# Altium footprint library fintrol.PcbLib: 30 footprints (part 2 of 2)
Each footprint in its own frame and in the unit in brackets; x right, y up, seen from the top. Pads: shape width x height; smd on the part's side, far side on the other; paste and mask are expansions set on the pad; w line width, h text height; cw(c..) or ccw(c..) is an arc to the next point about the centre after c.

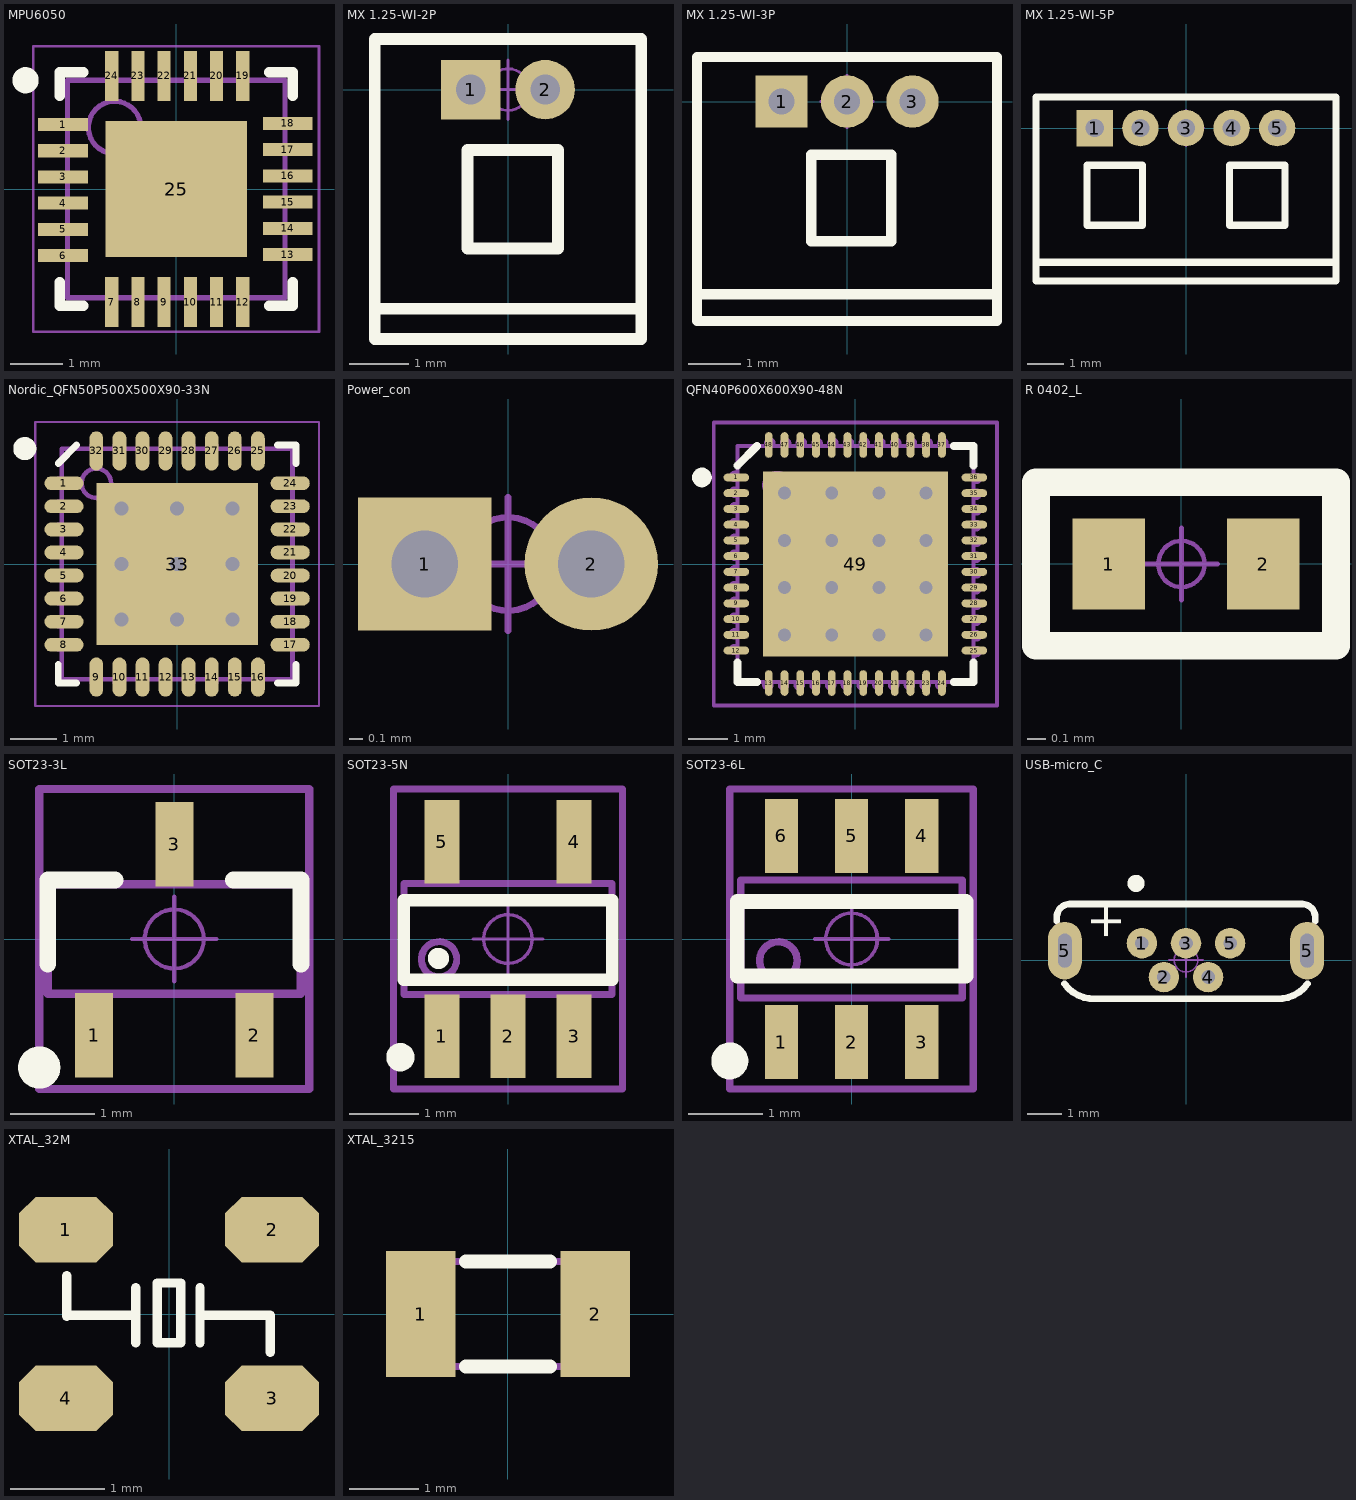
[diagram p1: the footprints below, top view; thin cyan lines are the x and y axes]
## MPU6050 [mm] "QFN, 24-Leads, Body 4.00x4.00mm, Pitch 0.50mm, Thermal Pad 2.70x2.60mm, IPC Medium Density"
height 0.9
pads (25):
  rect 0.95x0.25 smd: 1(-2.159,1.23) 2(-2.159,0.73) 3(-2.159,0.23) 4(-2.159,-0.27) 5(-2.159,-0.77) 6(-2.159,-1.27) 13(2.127,-1.25) 14(2.127,-0.75) 15(2.127,-0.25) 16(2.127,0.25) 17(2.127,0.75) 18(2.127,1.25)
  rect 0.25x0.95 smd: 7(-1.23,-2.159) 8(-0.73,-2.159) 9(-0.23,-2.159) 10(0.27,-2.159) 11(0.77,-2.159) 12(1.27,-2.159) 19(1.27,2.159) 20(0.77,2.159) 21(0.27,2.159) 22(-0.23,2.159) 23(-0.73,2.159) 24(-1.23,2.159)
  rect 2.7x2.6 smd: 25(0,0)
Top Overlay:
  circle w0.25: c-2.875,2.075 r0.125
  lines w0.2: -2.225,-1.775 -2.225,-2.225 -1.775,-2.225 ; -2.225,1.775 -2.225,2.225 -1.775,2.225 ; 1.775,-2.225 2.225,-2.225 2.225,-1.775 ; 1.775,2.225 2.225,2.225 2.225,1.775
Mechanical 13:
  circle w0.1: c-1.175,1.175 r0.5
  lines w0.1: -2.075,-2.075 2.075,-2.075 2.075,2.075 -2.075,2.075 -2.075,-2.075
Mechanical 15:
  lines w0.05: -2.725,-2.725 2.725,-2.725 2.725,2.725 -2.725,2.725 -2.725,-2.725
  lines w0.1: -0.5,0 0.5,0 ; 0,-0.5 0,0.5
3D body: height 0.9, standoff 0.01, extent -2.075,-2.075 2.075,2.075

## MX 1.25-WI-2P [mm] "长：4.25mm，宽：1.8mm，高：3.3mm"
pads (2):
  rect 1x1 hole 0.5: 1(-0.625,0)
  round 1 hole 0.5: 2(0.625,0)
Top Overlay:
  lines w0.2: -2.239,-3.683 2.239,-3.683 ; -2.239,-4.191 -2.239,0.85 2.239,0.85 2.239,-4.191 -2.239,-4.191 ; -0.682,-2.667 -0.682,-1.016 0.842,-1.016 0.842,-2.667 -0.682,-2.667
Mechanical 15:
  circle w0.05: c0,0 r0.35
  lines w0.05: -0.5,0 0.5,0 ; 0,-0.5 0,0.5
3D body "MOLEX1.25-WI-2P.STEP": height 3.35, standoff -2.1, extent -2.125,-4.05 2.125,0.85

## MX 1.25-WI-3P [mm] "长：5.5mm，宽：1.8mm，高：3.3mm"
pads (3):
  rect 1x1 hole 0.5: 1(-1.25,0)
  round 1 hole 0.5: 2(0,0) 3(1.25,0)
Top Overlay:
  lines w0.2: -2.864,-3.683 2.864,-3.683 ; -2.864,-4.191 2.864,-4.191 2.864,0.85 -2.864,0.85 -2.864,-4.191 ; -0.682,-2.667 0.842,-2.667 0.842,-1.016 -0.682,-1.016 -0.682,-2.667
Mechanical 15:
  circle w0.05: c0,0 r0.35
  lines w0.05: -0.5,0 0.5,0 ; 0,-0.5 0,0.5
3D body "MOLEX1.25-WI-3P.STEP": height 3.35, standoff -2.1, extent -2.75,-4.05 2.75,0.85

## MX 1.25-WI-5P [mm] "长：8mm，宽：1.8mm，高：3.3mm"
pads (5):
  rect 1x1 hole 0.5: 1(-2.5,0)
  round 1 hole 0.5: 2(-1.25,0) 3(0,0) 4(1.25,0) 5(2.5,0)
Top Overlay:
  lines w0.2: -4.114,-3.683 4.114,-3.683 ; -4.114,-4.191 4.114,-4.191 4.114,0.85 -4.114,0.85 -4.114,-4.191 ; -2.717,-2.667 -2.717,-1.016 -1.193,-1.016 -1.193,-2.667 -2.717,-2.667 ; 1.193,-2.667 1.193,-1.016 2.717,-1.016 2.717,-2.667 1.193,-2.667
Mechanical 15:
  circle w0.05: c0,0 r0.35
  lines w0.05: -0.5,0 0.5,0 ; 0,-0.5 0,0.5
3D body "MOLEX1.25-WI-5P.STEP": height 3.35, standoff -2.1, extent -4,-4.05 4,0.85

## Nordic_QFN50P500X500X90-33N [mm]
pads (33):
  oval 0.85x0.3 smd mask+0.076: 1(-2.45,1.75) 2(-2.45,1.25) 3(-2.45,0.75) 4(-2.45,0.25) 5(-2.45,-0.25) 6(-2.45,-0.75) 7(-2.45,-1.25) 8(-2.45,-1.75) 17(2.45,-1.75) 18(2.45,-1.25) 19(2.45,-0.75) 20(2.45,-0.25) 21(2.45,0.25) 22(2.45,0.75) 23(2.45,1.25) 24(2.45,1.75)
  oval 0.3x0.85 smd mask+0.076: 9(-1.75,-2.45) 10(-1.25,-2.45) 11(-0.75,-2.45) 12(-0.25,-2.45) 13(0.25,-2.45) 14(0.75,-2.45) 15(1.25,-2.45) 16(1.75,-2.45) 25(1.75,2.45) 26(1.25,2.45) 27(0.75,2.45) 28(0.25,2.45) 29(-0.25,2.45) 30(-0.75,2.45) 31(-1.25,2.45) 32(-1.75,2.45)
  rect 3.5x3.5 smd: 33(0,0)
via 1.2,1.2 diameter 0.61 hole 0.305
via 1.2,0 diameter 0.61 hole 0.305
via 1.2,-1.2 diameter 0.61 hole 0.305
via 0,-1.2 diameter 0.61 hole 0.305
via -1.2,-1.2 diameter 0.61 hole 0.305
via -1.2,0 diameter 0.61 hole 0.305
via -1.2,1.2 diameter 0.61 hole 0.305
via 0,1.2 diameter 0.61 hole 0.305
via 0,0 diameter 0.61 hole 0.305
Top Overlay:
  circle w0.25: c-3.3,2.5 r0.125
  lines w0.15: -2.575,-2.175 -2.575,-2.575 -2.175,-2.575 ; -2.575,2.175 -2.175,2.575 ; 2.175,-2.575 2.575,-2.575 2.575,-2.175 ; 2.175,2.575 2.575,2.575 2.575,2.175
Mechanical 7:
  circle w0.1: c-1.75,1.75 r0.32
  lines w0.1: -2.5,-1.845 -2.571,-1.845 cw(c-2.571,-1.75) -2.571,-1.655 -2.5,-1.655 ; -2.5,-1.345 -2.571,-1.345 cw(c-2.571,-1.25) -2.571,-1.155 -2.5,-1.155 ; -2.5,-0.845 -2.571,-0.845 cw(c-2.571,-0.75) -2.571,-0.655 -2.5,-0.655 ; -2.5,-0.345 -2.571,-0.345 cw(c-2.571,-0.25) -2.571,-0.155 -2.5,-0.155 ; -2.5,0.155 -2.571,0.155 cw(c-2.571,0.25) -2.571,0.345 -2.5,0.345 ; -2.5,0.655 -2.571,0.655 cw(c-2.571,0.75) -2.571,0.845 -2.5,0.845 ; -2.5,1.155 -2.571,1.155 cw(c-2.571,1.25) -2.571,1.345 -2.5,1.345 ; -2.5,1.655 -2.571,1.655 cw(c-2.571,1.75) -2.571,1.845 -2.5,1.845 ; -1.845,-2.5 -1.845,-2.571 ccw(c-1.75,-2.571) -1.655,-2.571 -1.655,-2.5 ; -1.845,2.5 -1.845,2.571 cw(c-1.75,2.571) -1.655,2.571 -1.655,2.5 ; -1.345,-2.5 -1.345,-2.571 ccw(c-1.25,-2.571) -1.155,-2.571 -1.155,-2.5 ; -1.345,2.5 -1.345,2.571 cw(c-1.25,2.571) -1.155,2.571 -1.155,2.5 ; -0.845,-2.5 -0.845,-2.571 ccw(c-0.75,-2.571) -0.655,-2.571 -0.655,-2.5 ; -0.845,2.5 -0.845,2.571 cw(c-0.75,2.571) -0.655,2.571 -0.655,2.5 ; -0.345,-2.5 -0.345,-2.571 ccw(c-0.25,-2.571) -0.155,-2.571 -0.155,-2.5 ; -0.345,2.5 -0.345,2.571 cw(c-0.25,2.571) -0.155,2.571 -0.155,2.5 ; 0.155,-2.5 0.155,-2.571 ccw(c0.25,-2.571) 0.345,-2.571 0.345,-2.5 ; 0.155,2.5 0.155,2.571 cw(c0.25,2.571) 0.345,2.571 0.345,2.5 ; 0.655,-2.5 0.655,-2.571 ccw(c0.75,-2.571) 0.845,-2.571 0.845,-2.5 ; 0.655,2.5 0.655,2.571 cw(c0.75,2.571) 0.845,2.571 0.845,2.5 ; 1.155,-2.5 1.155,-2.571 ccw(c1.25,-2.571) 1.345,-2.571 1.345,-2.5 ; 1.155,2.5 1.155,2.571 cw(c1.25,2.571) 1.345,2.571 1.345,2.5 ; 1.655,-2.5 1.655,-2.571 ccw(c1.75,-2.571) 1.845,-2.571 1.845,-2.5 ; 1.655,2.5 1.655,2.571 cw(c1.75,2.571) 1.845,2.571 1.845,2.5 ; 2.5,-1.845 2.571,-1.845 ccw(c2.571,-1.75) 2.571,-1.655 2.5,-1.655 ; 2.5,-1.345 2.571,-1.345 ccw(c2.571,-1.25) 2.571,-1.155 2.5,-1.155 ; 2.5,-0.845 2.571,-0.845 ccw(c2.571,-0.75) 2.571,-0.655 2.5,-0.655 ; 2.5,-0.345 2.571,-0.345 ccw(c2.571,-0.25) 2.571,-0.155 2.5,-0.155 ; 2.5,0.155 2.571,0.155 ccw(c2.571,0.25) 2.571,0.345 2.5,0.345 ; 2.5,0.655 2.571,0.655 ccw(c2.571,0.75) 2.571,0.845 2.5,0.845 ; 2.5,1.155 2.571,1.155 ccw(c2.571,1.25) 2.571,1.345 2.5,1.345 ; 2.5,1.655 2.571,1.655 ccw(c2.571,1.75) 2.571,1.845 2.5,1.845 ; -2.5,-2.5 2.5,-2.5 2.5,2.5 -2.5,2.5 -2.5,-2.5
  text ".Designator" at -0.879,-0.131 h0.38
Mechanical 15:
  lines w0.05: -3.075,-3.075 -3.075,3.075 3.075,3.075 3.075,-3.075 -3.075,-3.075
  lines w0.1: -0.5,0 0.5,0 ; 0,-0.5 0,0.5
3D body "QFN50P500X500X90_HS-33N.step": height 0.9, standoff 0, extent -2.501,-2.501 2.501,2.501

## Power_con [mm] "长：4.25mm，宽：1.8mm，高：3.3mm"
pads (2):
  rect 1x1 hole 0.5: 1(-0.625,0)
  round 1 hole 0.5: 2(0.625,0)
Mechanical 15:
  circle w0.05: c0,0 r0.35
  lines w0.05: -0.5,0 0.5,0 ; 0,-0.5 0,0.5

## QFN40P600X600X90-48N [mm]
pads (49):
  oval 0.65x0.2 smd: 1(-3.025,2.2) 2(-3.025,1.8) 3(-3.025,1.4) 4(-3.025,1) 5(-3.025,0.6) 6(-3.025,0.2) 7(-3.025,-0.2) 8(-3.025,-0.6) 9(-3.025,-1) 10(-3.025,-1.4) 11(-3.025,-1.8) 12(-3.025,-2.2) 25(3.025,-2.2) 26(3.025,-1.8) 27(3.025,-1.4) 28(3.025,-1) 29(3.025,-0.6) 30(3.025,-0.2) 31(3.025,0.2) 32(3.025,0.6) 33(3.025,1) 34(3.025,1.4) 35(3.025,1.8) 36(3.025,2.2)
  oval 0.2x0.65 smd: 13(-2.2,-3.025) 14(-1.8,-3.025) 15(-1.4,-3.025) 16(-1,-3.025) 17(-0.6,-3.025) 18(-0.2,-3.025) 19(0.2,-3.025) 20(0.6,-3.025) 21(1,-3.025) 22(1.4,-3.025) 23(1.8,-3.025) 24(2.2,-3.025) 37(2.2,3.025) 38(1.8,3.025) 39(1.4,3.025) 40(1,3.025) 41(0.6,3.025) 42(0.2,3.025) 43(-0.2,3.025) 44(-0.6,3.025) 45(-1,3.025) 46(-1.4,3.025) 47(-1.8,3.025) 48(-2.2,3.025)
  rect 4.7x4.7 smd: 49(0,0)
via -1.8,1.8 diameter 0.66 hole 0.33
via -0.6,1.8 diameter 0.66 hole 0.33
via 0.6,1.8 diameter 0.66 hole 0.33
via 1.8,1.8 diameter 0.66 hole 0.33
via -1.8,0.6 diameter 0.66 hole 0.33
via -0.6,0.6 diameter 0.66 hole 0.33
via 0.6,0.6 diameter 0.66 hole 0.33
via 1.8,0.6 diameter 0.66 hole 0.33
via -1.8,-0.6 diameter 0.66 hole 0.33
via -0.6,-0.6 diameter 0.66 hole 0.33
via 0.6,-0.6 diameter 0.66 hole 0.33
via 1.8,-0.6 diameter 0.66 hole 0.33
via -1.8,-1.8 diameter 0.66 hole 0.33
via -0.6,-1.8 diameter 0.66 hole 0.33
via 0.6,-1.8 diameter 0.66 hole 0.33
via 1.8,-1.8 diameter 0.66 hole 0.33
Top Overlay:
  circle w0.25: c-3.9,2.2 r0.125
  lines w0.2: -3,-2.5 -3,-3 -2.5,-3 ; -3,2.5 -2.5,3 ; 2.5,-3 3,-3 3,-2.5 ; 2.5,3 3,3 3,2.5
Mechanical 7:
  circle w0.1: c-2,2 r0.32
  lines w0.1: -3,-2.269 -3.071,-2.269 cw(c-3.071,-2.174) -3.071,-2.079 -3,-2.079 ; -3,-1.869 -3.071,-1.869 cw(c-3.071,-1.774) -3.071,-1.679 -3,-1.679 ; -3,-1.469 -3.071,-1.469 cw(c-3.071,-1.374) -3.071,-1.279 -3,-1.279 ; -3,-1.069 -3.071,-1.069 cw(c-3.071,-0.974) -3.071,-0.879 -3,-0.879 ; -3,-0.669 -3.071,-0.669 cw(c-3.071,-0.574) -3.071,-0.479 -3,-0.479 ; -3,-0.269 -3.071,-0.269 cw(c-3.071,-0.174) -3.071,-0.079 -3,-0.079 ; -3,0.131 -3.071,0.131 cw(c-3.071,0.226) -3.071,0.321 -3,0.321 ; -3,0.531 -3.071,0.531 cw(c-3.071,0.626) -3.071,0.721 -3,0.721 ; -3,0.931 -3.071,0.931 cw(c-3.071,1.026) -3.071,1.121 -3,1.121 ; -3,1.331 -3.071,1.331 cw(c-3.071,1.426) -3.071,1.521 -3,1.521 ; -3,1.731 -3.071,1.731 cw(c-3.071,1.826) -3.071,1.921 -3,1.921 ; -3,2.131 -3.071,2.131 cw(c-3.071,2.226) -3.071,2.321 -3,2.321 ; -2.321,-3 -2.321,-3.071 ccw(c-2.226,-3.071) -2.131,-3.071 -2.131,-3 ; -2.269,3 -2.269,3.071 cw(c-2.174,3.071) -2.079,3.071 -2.079,3 ; -1.921,-3 -1.921,-3.071 ccw(c-1.826,-3.071) -1.731,-3.071 -1.731,-3 ; -1.869,3 -1.869,3.071 cw(c-1.774,3.071) -1.679,3.071 -1.679,3 ; -1.521,-3 -1.521,-3.071 ccw(c-1.426,-3.071) -1.331,-3.071 -1.331,-3 ; -1.469,3 -1.469,3.071 cw(c-1.374,3.071) -1.279,3.071 -1.279,3 ; -1.121,-3 -1.121,-3.071 ccw(c-1.026,-3.071) -0.931,-3.071 -0.931,-3 ; -1.069,3 -1.069,3.071 cw(c-0.974,3.071) -0.879,3.071 -0.879,3 ; -0.721,-3 -0.721,-3.071 ccw(c-0.626,-3.071) -0.531,-3.071 -0.531,-3 ; -0.669,3 -0.669,3.071 cw(c-0.574,3.071) -0.479,3.071 -0.479,3 ; -0.321,-3 -0.321,-3.071 ccw(c-0.226,-3.071) -0.131,-3.071 -0.131,-3 ; -0.269,3 -0.269,3.071 cw(c-0.174,3.071) -0.079,3.071 -0.079,3 ; 0.079,-3 0.079,-3.071 ccw(c0.174,-3.071) 0.269,-3.071 0.269,-3 ; 0.131,3 0.131,3.071 cw(c0.226,3.071) 0.321,3.071 0.321,3 ; 0.479,-3 0.479,-3.071 ccw(c0.574,-3.071) 0.669,-3.071 0.669,-3 ; 0.531,3 0.531,3.071 cw(c0.626,3.071) 0.721,3.071 0.721,3 ; 0.879,-3 0.879,-3.071 ccw(c0.974,-3.071) 1.069,-3.071 1.069,-3 ; 0.931,3 0.931,3.071 cw(c1.026,3.071) 1.121,3.071 1.121,3 ; 1.279,-3 1.279,-3.071 ccw(c1.374,-3.071) 1.469,-3.071 1.469,-3 ; 1.331,3 1.331,3.071 cw(c1.426,3.071) 1.521,3.071 1.521,3 ; 1.679,-3 1.679,-3.071 ccw(c1.774,-3.071) 1.869,-3.071 1.869,-3 ; 1.731,3 1.731,3.071 cw(c1.826,3.071) 1.921,3.071 1.921,3 ; 2.079,-3 2.079,-3.071 ccw(c2.174,-3.071) 2.269,-3.071 2.269,-3 ; 2.131,3 2.131,3.071 cw(c2.226,3.071) 2.321,3.071 2.321,3 ; 3,-2.321 3.071,-2.321 ccw(c3.071,-2.226) 3.071,-2.131 3,-2.131 ; 3,-1.921 3.071,-1.921 ccw(c3.071,-1.826) 3.071,-1.731 3,-1.731 ; 3,-1.521 3.071,-1.521 ccw(c3.071,-1.426) 3.071,-1.331 3,-1.331 ; 3,-1.121 3.071,-1.121 ccw(c3.071,-1.026) 3.071,-0.931 3,-0.931 ; 3,-0.721 3.071,-0.721 ccw(c3.071,-0.626) 3.071,-0.531 3,-0.531 ; 3,-0.321 3.071,-0.321 ccw(c3.071,-0.226) 3.071,-0.131 3,-0.131 ; 3,0.079 3.071,0.079 ccw(c3.071,0.174) 3.071,0.269 3,0.269 ; 3,0.479 3.071,0.479 ccw(c3.071,0.574) 3.071,0.669 3,0.669 ; 3,0.879 3.071,0.879 ccw(c3.071,0.974) 3.071,1.069 3,1.069 ; 3,1.279 3.071,1.279 ccw(c3.071,1.374) 3.071,1.469 3,1.469 ; 3,1.679 3.071,1.679 ccw(c3.071,1.774) 3.071,1.869 3,1.869 ; 3,2.079 3.071,2.079 ccw(c3.071,2.174) 3.071,2.269 3,2.269 ; -3,-3 -3,3 3,3 3,-3 -3,-3
  text ".Designator" at -1.1,-0.2 h0.38
Mechanical 15:
  lines w0.1: -0.5,0 0.5,0 ; 0,-0.5 0,0.5 ; -3.6,-3.6 -3.6,3.6 3.6,3.6 3.6,-3.6 -3.6,-3.6
3D body "User Library-QFN48.step": height 0.86, standoff -0.01, extent -3.02,-3.02 3.02,3.02

## R 0402_L [mm] "1/16W贴片电阻"
pads (2):
  rect 0.4x0.5 smd: 1(-0.4,0) 2(0.45,0)
Top Overlay:
  lines w0.152: -0.8,-0.45 0.85,-0.45 0.85,0.45 -0.8,0.45 -0.8,-0.45
Mechanical 15:
  circle w0.025: c0,0 r0.127
  lines w0.025: -0.2,0 0.2,0 ; 0,-0.2 0,0.2
3D body "R 0402.STEP": height 0.3, standoff 0, extent -0.5,-0.25 0.5,0.25

## SOT23-3L [mm] "3x1.3x1mm(长宽高)"
height 1.1
pads (3):
  rect 0.45x1 smd: 1(-0.95,-1.143) 2(0.95,-1.143) 3(0,1.125)
Top Overlay:
  circle w0.25: c-1.6,-1.524 r0.125
  lines w0.2: -1.5,-0.3 -1.5,0.7 -0.7,0.7 ; 0.7,0.7 1.5,0.7 1.5,-0.3
Mechanical 13:
  lines w0.1: -1.5,-0.65 -1.5,0.65 1.5,0.65 1.5,-0.65 -1.5,-0.65
Mechanical 15:
  circle w0.05: c0,0 r0.35
  lines w0.05: -0.5,0 0.5,0 ; 0,-0.5 0,0.5
  lines w0.1: -1.6,-1.778 -1.6,1.778 1.6,1.778 1.6,-1.778 -1.6,-1.778
3D body "SOT23-3.STEP": height 1.05, standoff 0, extent -1.5,-1.2 1.5,1.2

## SOT23-5N [mm] "3x1.6x1.1mm(长宽高)"
pads (5):
  rect 0.5x1.2 smd: 1(-0.95,-1.4) 2(0,-1.4) 3(0.95,-1.4) 4(0.95,1.4) 5(-0.95,1.4)
Top Overlay:
  circle w0.254: c-1.001,-0.279 r0.025
  circle w0.254: c-1.549,-1.702 r0.076
  lines w0.178: -1.5,-0.584 1.5,-0.584 1.5,0.559 -1.5,0.559 -1.5,-0.584
Mechanical 13:
  circle w0.1: c-0.992,-0.292 r0.254
  lines w0.1: -1.5,-0.8 1.5,-0.8 1.5,0.8 -1.5,0.8 -1.5,-0.8
Mechanical 15:
  circle w0.05: c0,0 r0.35
  lines w0.05: -0.5,0 0.5,0 ; 0,-0.5 0,0.5
  lines w0.1: -1.651,-2.159 -1.651,2.159 1.651,2.159 1.651,-2.159 -1.651,-2.159
3D body "SOT23-5.STEP": height 1.15, standoff -0.03, extent -1.5,-1.403 1.5,1.403

## SOT23-6L [mm] "3x1.6x1.1mm(长宽高)"
height 1.45
pads (6):
  rect 0.45x1 smd: 1(-0.95,-1.397) 2(0,-1.397) 3(0.95,-1.397) 4(0.95,1.397) 5(0,1.397) 6(-0.95,1.397)
Top Overlay:
  circle w0.25: c-1.65,-1.651 r0.125
  lines w0.2: -1.55,-0.5 1.55,-0.5 1.55,0.508 -1.55,0.508 -1.55,-0.5
Mechanical 13:
  circle w0.1: c-0.992,-0.292 r0.254
  lines w0.1: -1.5,-0.8 -1.5,0.8 1.5,0.8 1.5,-0.8 -1.5,-0.8
Mechanical 15:
  circle w0.05: c0,0 r0.35
  lines w0.05: -0.5,0 0.5,0 ; 0,-0.5 0,0.5
  lines w0.1: -1.65,-2.032 -1.65,2.032 1.65,2.032 1.65,-2.032 -1.65,-2.032
3D body "SOT23-6.STEP": height 1.15, standoff -0.03, extent -1.5,-1.404 1.5,1.403

## USB-micro_C [mm] "micro型USB ，5.7*7.8*2.5mm"
pads (7):
  round 0.9 hole 0.4: 1(-1.3,0.5) 2(-0.65,-0.5) 3(0,0.5) 4(0.65,-0.5) 5(1.3,0.5)
  oval 1x1.7 hole 0.4 slot 1 at 90 deg: 5(-3.575,0.28) 5(3.575,0.28)
Top Overlay:
  circle w0.254: c-1.473,2.261 r0.127
  lines w0.2: -3.81,1.143 -3.81,1.27 cw(c-3.429,1.27) -3.429,1.651 -3.175,1.651 -2.794,1.651 2.794,1.651 3.175,1.651 3.429,1.651 cw(c3.429,1.27) 3.81,1.27 3.81,1.143 ; -3.587,-0.697 ccw(c-2.718,-0.076) -2.667,-1.143 ; -2.629,-1.143 -2.413,-1.143 2.413,-1.143 2.667,-1.143 ccw(c2.718,-0.076) 3.587,-0.697
  text "+" at -1.905,0.559 h1.02
Mechanical 15:
  circle w0.05: c0,0 r0.35
  lines w0.05: -0.5,0 0.5,0 ; 0,-0.5 0,0.5
3D body "USB micro_C.STEP": height 5.65, standoff -1.55, extent -4.001,-1.207 4.001,1.767

## XTAL_32M [mm]
pads (4):
  oct 1x0.7 smd: 1(-1.1,0.9) 2(1.1,0.9) 3(1.1,-0.9) 4(-1.1,-0.9)
Top Overlay:
  lines w0.1: -1.092,0.406 -1.092,-0.025 -1.079,-0.013 -0.356,-0.013 ; -0.356,-0.305 -0.356,0.279 ; 0.33,-0.305 0.33,0.279 ; 0.33,-0.013 1.079,-0.013 1.079,-0.406 ; -0.127,-0.305 -0.127,0.33 0.127,0.33 0.127,-0.102 0.127,-0.305 -0.127,-0.305

## XTAL_3215 [mm]
pads (2):
  rect 1x1.8 smd: 1(-1.25,0) 2(1.25,0)
Top Overlay:
  lines w0.2: -0.6,-0.75 0.6,-0.75 ; -0.6,0.75 0.6,0.75
Mechanical 7:
  lines w0.1: -1.6,-0.75 -1.6,0.75 1.6,0.75 1.6,-0.75 -1.6,-0.75
  text ".Designator" at -0.845,-0.133 h0.38
Mechanical 15:
  lines w0.1: -1.6,-0.55 cw(c-1.6,-0.75) -1.4,-0.75 1.4,-0.75 cw(c1.6,-0.75) 1.6,-0.55 1.6,0.55 cw(c1.6,0.75) 1.4,0.75 -1.4,0.75 cw(c-1.6,0.75) -1.6,0.55 -1.6,-0.55
3D body: height 0.81, standoff 0.15, extent -1.2,-0.6 1.2,0.6
3D body "User Library-Siward_SX3215.step": height 0.81, standoff 0, extent -1.6,-0.75 1.6,0.75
